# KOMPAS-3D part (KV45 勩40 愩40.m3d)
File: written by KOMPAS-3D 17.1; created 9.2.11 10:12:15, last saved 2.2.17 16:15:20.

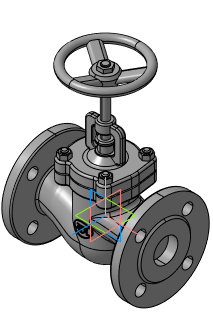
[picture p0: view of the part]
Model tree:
1. Плоскость XY
2. Плоскость ZX
3. Плоскость ZY
4. Ось X
5. Ось Y
6. Ось Z
7. Начало координат
8. Операция без истории:4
